(* Logix 5000 AddOnInstructionDefinition export HI1769_AOI_FLT; software revision 32.00; part 2 of 2 *)
(* tags used below, declared in another part *)
   Inp_hi1769 : HI:1769_xWS_ChannelNOCMD_FP_r3:I:0;
   Out_hi1769 : HI:1769_xWS_Channel:O:0;
   cal_hi_cmd : BOOL;   // trigger the cal high command
   cal_low_cmd : BOOL;   // trigger the cal low command
   cmd_status : INT;
   cal_hi_ctrl : DINT;
   cal_lo_ctrl : DINT;
   CalHI_cmd_reset_timer : TIMER;
   Status_Return : HardyCmdResult;
(* HI1769_AOI_FLT, continued *)

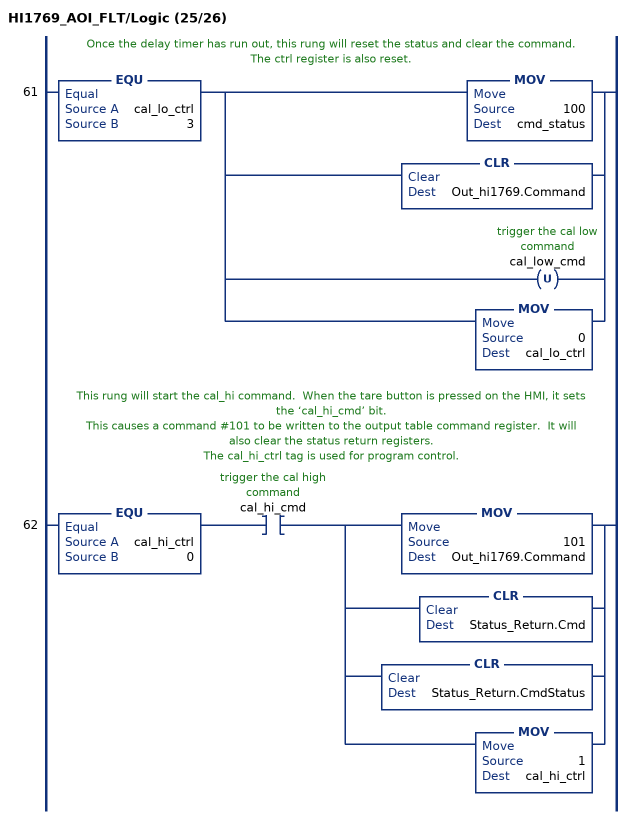
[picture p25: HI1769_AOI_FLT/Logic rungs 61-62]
   // Once the delay timer has run out, this rung will reset the status and clear the command.
   // The ctrl register is also reset.
   61: EQU(cal_lo_ctrl,3)[MOV(100,cmd_status) ,CLR(Out_hi1769.Command) ,OTU(cal_low_cmd) ,MOV(0,cal_lo_ctrl) ];
   // This rung will start the cal_hi command.  When the tare button is pressed on the HMI, it sets the ‘cal_hi_cmd’ bit.
   // This causes a command #101 to be written to the output table command register.  It will also clear the status return registers.
   // The cal_hi_ctrl tag is used for program control.
   62: EQU(cal_hi_ctrl,0)XIC(cal_hi_cmd)[MOV(101,Out_hi1769.Command) ,CLR(Status_Return.Cmd) ,CLR(Status_Return.CmdStatus) ,MOV(1,cal_hi_ctrl) ];
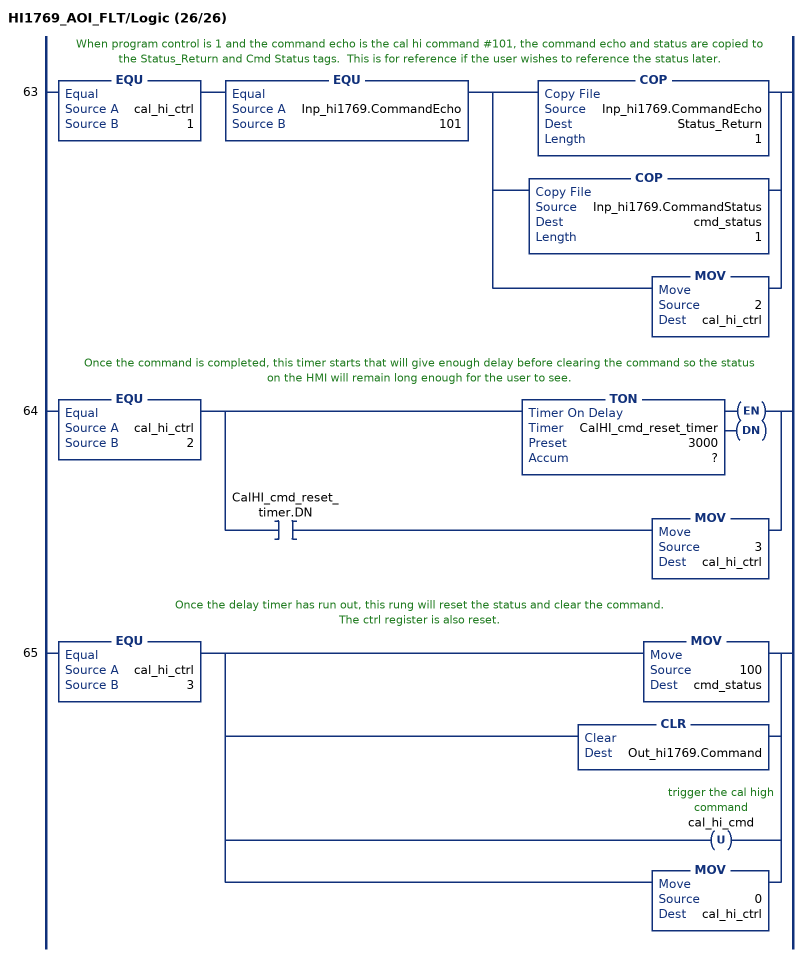
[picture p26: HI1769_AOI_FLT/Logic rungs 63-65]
   // When program control is 1 and the command echo is the cal hi command #101, the command echo and status are copied to the Status_Return and Cmd Status tags.  This is for reference if the user wishes to reference the status later.
   63: EQU(cal_hi_ctrl,1)EQU(Inp_hi1769.CommandEcho,101)[COP(Inp_hi1769.CommandEcho,Status_Return,1) ,COP(Inp_hi1769.CommandStatus,cmd_status,1) ,MOV(2,cal_hi_ctrl) ];
   // Once the command is completed, this timer starts that will give enough delay before clearing the command so the status on the HMI will remain long enough for the user to see.
   64: EQU(cal_hi_ctrl,2)[TON(CalHI_cmd_reset_timer,?,?) ,XIC(CalHI_cmd_reset_timer.DN) MOV(3,cal_hi_ctrl) ];
   // Once the delay timer has run out, this rung will reset the status and clear the command.
   // The ctrl register is also reset.
   65: EQU(cal_hi_ctrl,3)[MOV(100,cmd_status) ,CLR(Out_hi1769.Command) ,OTU(cal_hi_cmd) ,MOV(0,cal_hi_ctrl) ];
END_ROUTINE
END_ADD_ON_INSTRUCTION
